VERSION 5.7 ;
  NOWIREEXTENSIONATPIN ON ;
  DIVIDERCHAR "/" ;
  BUSBITCHARS "[]" ;
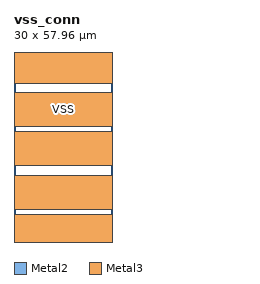
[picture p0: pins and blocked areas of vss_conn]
MACRO vss_conn
  CLASS BLOCK ;
  FOREIGN vss_conn ;
  ORIGIN 0.000 0.000 ;
  SIZE 30.000 BY 57.960 ;
  PIN VSS
    DIRECTION INOUT ;
    USE GROUND ;
    PORT
      LAYER Metal2 ;
        RECT 0.000 48.460 30.000 57.960 ;
        RECT 0.000 35.310 30.000 45.560 ;
        RECT 0.000 23.460 30.000 33.710 ;
        RECT 0.000 9.930 30.000 20.180 ;
        RECT 0.000 0.000 30.000 8.330 ;
      LAYER Metal3 ;
        RECT 0.000 48.460 30.000 57.960 ;
        RECT 0.000 35.310 30.000 45.560 ;
        RECT 0.000 23.460 30.000 33.710 ;
        RECT 0.000 9.930 30.000 20.180 ;
        RECT 0.000 0.000 30.000 8.330 ;
    END
  END VSS
END vss_conn
END LIBRARY
